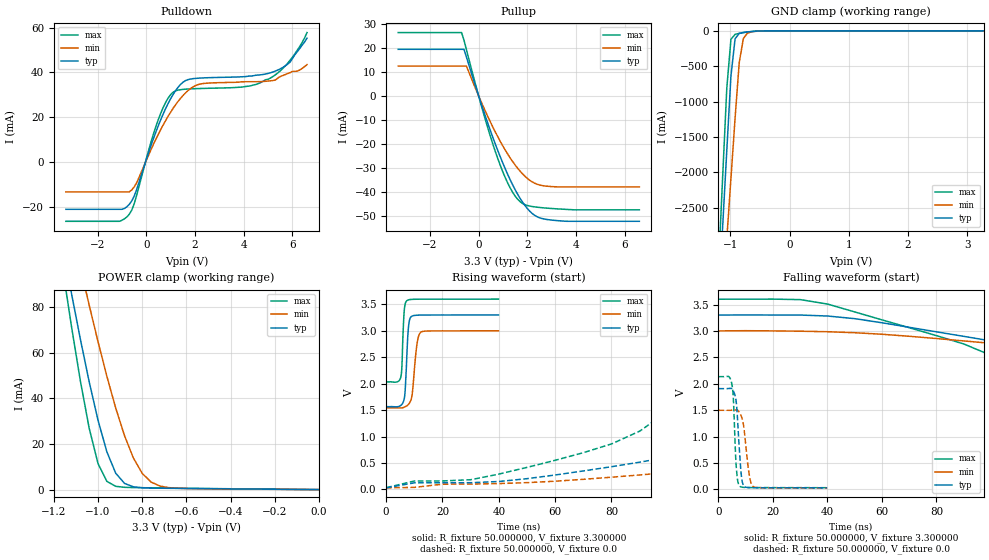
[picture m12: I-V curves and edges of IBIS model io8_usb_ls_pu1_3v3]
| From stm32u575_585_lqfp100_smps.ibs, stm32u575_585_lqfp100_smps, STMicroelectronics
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|   Model io8_usb_ls_pu1_3v3
[Model]  io8_usb_ls_pu1_3v3
Model_type I/O
Polarity   Non-Inverting
Enable   Active-Low
Vinl =   0.990000V
Vinh =   2.310000V
Vmeas =  1.650000V
Cref =   50.000000pF
Rref =   100.000000M
Vref =   0.0V
C_comp   7.156600pF   7.055100pF   7.302500pF
[Temperature Range]   25.000000   0.140000k   -40.000000
[Pullup Reference]   3.300000V   3.000000V   3.600000V
[Pulldown Reference]   0.0V   0.0V   0.0V
[POWER Clamp Reference]   3.300000V   3.000000V   3.600000V
[GND Clamp Reference]   0.0V   0.0V   0.0V
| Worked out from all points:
|   slope of the pulldown table from 0 to 0.495 V, typ, clamps not added: 32.6 ohm
|   slope of the pullup table from 0 to 0.495 V, typ, clamps not added: 33.3 ohm
|   GND clamp passes 1 mA (typ) near -0.45 V on its own axis
|   POWER clamp passes 1 mA (typ) near -0.82 V on its own axis
|   rising waveform, R_fixture 50.000000, V_fixture 3.300000: 20-80 % time 956ps typ, 1.52ns min, 696ps max; typ from 1.56 V to 3.3 V
|   rising waveform, R_fixture 50.000000, V_fixture 0.0: 20-80 % time 79.8ns typ, 122ns min, 53.7ns max; typ from 0.028 V to 1.91 V
|   falling waveform, R_fixture 50.000000, V_fixture 3.300000: 20-80 % time 79ns typ, 126ns min, 50.5ns max; typ from 3.3 V to 1.56 V
|   falling waveform, R_fixture 50.000000, V_fixture 0.0: 20-80 % time 1.41ns typ, 1.93ns min, 1.03ns max; typ from 1.91 V to 0.028 V
[Pulldown]
|Voltage   I(typ)   I(min)   I(max)
-3.3V     -21.05mA   -13.29mA   -26.4mA
-1.1V     -21.05mA   -13.29mA   -26.4mA
-700mV    -18.88mA   -13.29mA   -23.31mA
-500mV    -15.3mA    -11.15mA   -18.77mA
500mV     16.41mA    12.53mA    19.15mA
800mV     24mA       18.65mA    26.74mA
1.1V      30.16mA    23.96mA    31.17mA
1.5V      35.58mA    29.62mA    32.44mA
2.1V      37.42mA    34.5mA     32.8mA
4.7V      38.95mA    35.94mA    35.51mA
5.8V      43.68mA    39.48mA    44.06mA
6.6V      55.3mA     43.5mA     57.8mA
[Pullup]
|Voltage   I(typ)   I(min)   I(max)
-3.3V     19.37mA    12.38mA    26.36mA
-700mV    19.37mA    12.38mA    26.36mA
-600mV    19.37mA    12.38mA    23.18mA
-500mV    16.18mA    12.38mA    19.24mA
200mV     -6.183mA   -4.67mA    -7.277mA
700mV     -20.51mA   -15.36mA   -23.63mA
1.2V      -32.9mA    -24.4mA    -36.49mA
1.5V      -39.15mA   -28.88mA   -41.83mA
1.7V      -42.72mA   -31.41mA   -44.13mA
2.2V      -49.08mA   -35.91mA   -46.18mA
2.7V      -51.41mA   -37.59mA   -46.77mA
6.6V      -52.35mA   -38mA      -47.57mA
[GND_clamp]
|Voltage   I(typ)   I(min)   I(max)
-3.3V     -9.287A    -9.833A    -9.745A
-1.2V     -3.857A    -4.664A    -3.345A
-1.13V    -2.774A    -3.805A    -2.072A
-1.06V    -1.695A    -2.947A    -813.1mA
-990mV    -641.8mA   -2.091A    -120.9mA
-920mV    -113.3mA   -1.238A    -49.89mA
-850mV    -36.8mA    -452mA     -36.31mA
-780mV    -22.65mA   -108.9mA   -26.22mA
-710mV    -15.23mA   -32.27mA   -17.43mA
-570mV    -5.119mA   -7.032mA   -4.907mA
-360mV    -90.45uA   -461.6uA   -25.95uA
3.28V     0A         40.32nA    -16.18nA
[POWER_clamp]
|Voltage   I(typ)   I(min)   I(max)
-3.28V    1.357A     1.167A     1.667A
-1.16V    106.8mA    132.5mA    97.01mA
-1.12V    86.01mA    114.9mA    71.53mA
-1.08V    66.05mA    97.65mA    47.75mA
-1.04V    47.29mA    80.94mA    26.91mA
-1V       30.42mA    64.88mA    11.4mA
-960mV    16.55mA    49.71mA    3.613mA
-920mV    7.194mA    35.78mA    1.444mA
-840mV    1.226mA    13.85mA    893.5uA
-760mV    678.5uA    3.311mA    779.5uA
-640mV    531.4uA    582.4uA    631.9uA
0V        0A         50.32nA    0A
[Ramp]
| variable   typ   min   max
dV/dt_r  1.12714/79.37551n   0.88126/0.12198u   1.26169/53.32291n
dV/dt_f  1.04112/78.72168n   0.87408/0.12538u   0.93972/50.48360n
R_load = 50.000000
[Rising Waveform]
R_fixture= 50.000000
V_fixture= 3.300000
V_fixture_min= 3.000000
V_fixture_max= 3.600000
|time   V(typ)   V(min)   V(max)
0s        1.565V     1.543V     2.034V
5.205ns   1.589V     1.542V     2.126V
5.606ns   1.61V      1.542V     2.349V
6.326ns   1.692V     1.553V     3.312V
6.807ns   1.925V     1.564V     3.519V
7.848ns   3.025V     1.604V     3.585V
8.969ns   3.272V     1.72V      3.595V
10.89ns   3.295V     2.728V     3.598V
12.25ns   3.298V     2.972V     3.599V
39.88ns   3.3V       3V         3.6V
[Rising Waveform]
R_fixture= 50.000000
V_fixture= 0.0
V_fixture_min= 0.0
V_fixture_max= 0.0
|time   V(typ)   V(min)   V(max)
0s        28.43mV    28.34mV    31.59mV
30.03ns   125.7mV    99.41mV    182.5mV
80.08ns   429.6mV    230.1mV    861.2mV
110.1ns   709.9mV    366.9mV    1.846V
120.1ns   827.9mV    417.9mV    2.026V
170.2ns   1.72V      713.1mV    2.234V
200.2ns   1.889V     991.6mV    2.236V
250.2ns   1.932V     1.359V     2.232V
360.4ns   1.933V     1.48V      2.221V
4.985us   1.907V     1.497V     2.135V
[Falling Waveform]
R_fixture= 50.000000
V_fixture= 3.300000
V_fixture_min= 3.000000
V_fixture_max= 3.600000
|time   V(typ)   V(min)   V(max)
0s        3.3V       3V         3.6V
40.04ns   3.282V     2.985V     3.509V
90.09ns   2.897V     2.81V      2.752V
120.1ns   2.623V     2.67V      1.965V
140.1ns   2.379V     2.57V      1.842V
170.2ns   1.77V      2.404V     1.86V
200.2ns   1.572V     2.177V     1.886V
270.3ns   1.537V     1.685V     1.93V
400.4ns   1.547V     1.553V     1.98V
4.985us   1.565V     1.543V     2.034V
[Falling Waveform]
R_fixture= 50.000000
V_fixture= 0.0
V_fixture_min= 0.0
V_fixture_max= 0.0
|time   V(typ)   V(min)   V(max)
0s        1.907V     1.497V     2.135V
4.885ns   1.906V     1.498V     2V
5.445ns   1.865V     1.501V     1.727V
6.486ns   1.662V     1.504V     452.5mV
7.047ns   1.279V     1.497V     164.6mV
7.848ns   619.9mV    1.443V     58.22mV
8.969ns   98.04mV    1.279V     39.05mV
11.29ns   32.96mV    273.7mV    34.34mV
12.65ns   30.93mV    56.64mV    33.57mV
39.88ns   28.43mV    28.34mV    31.59mV
